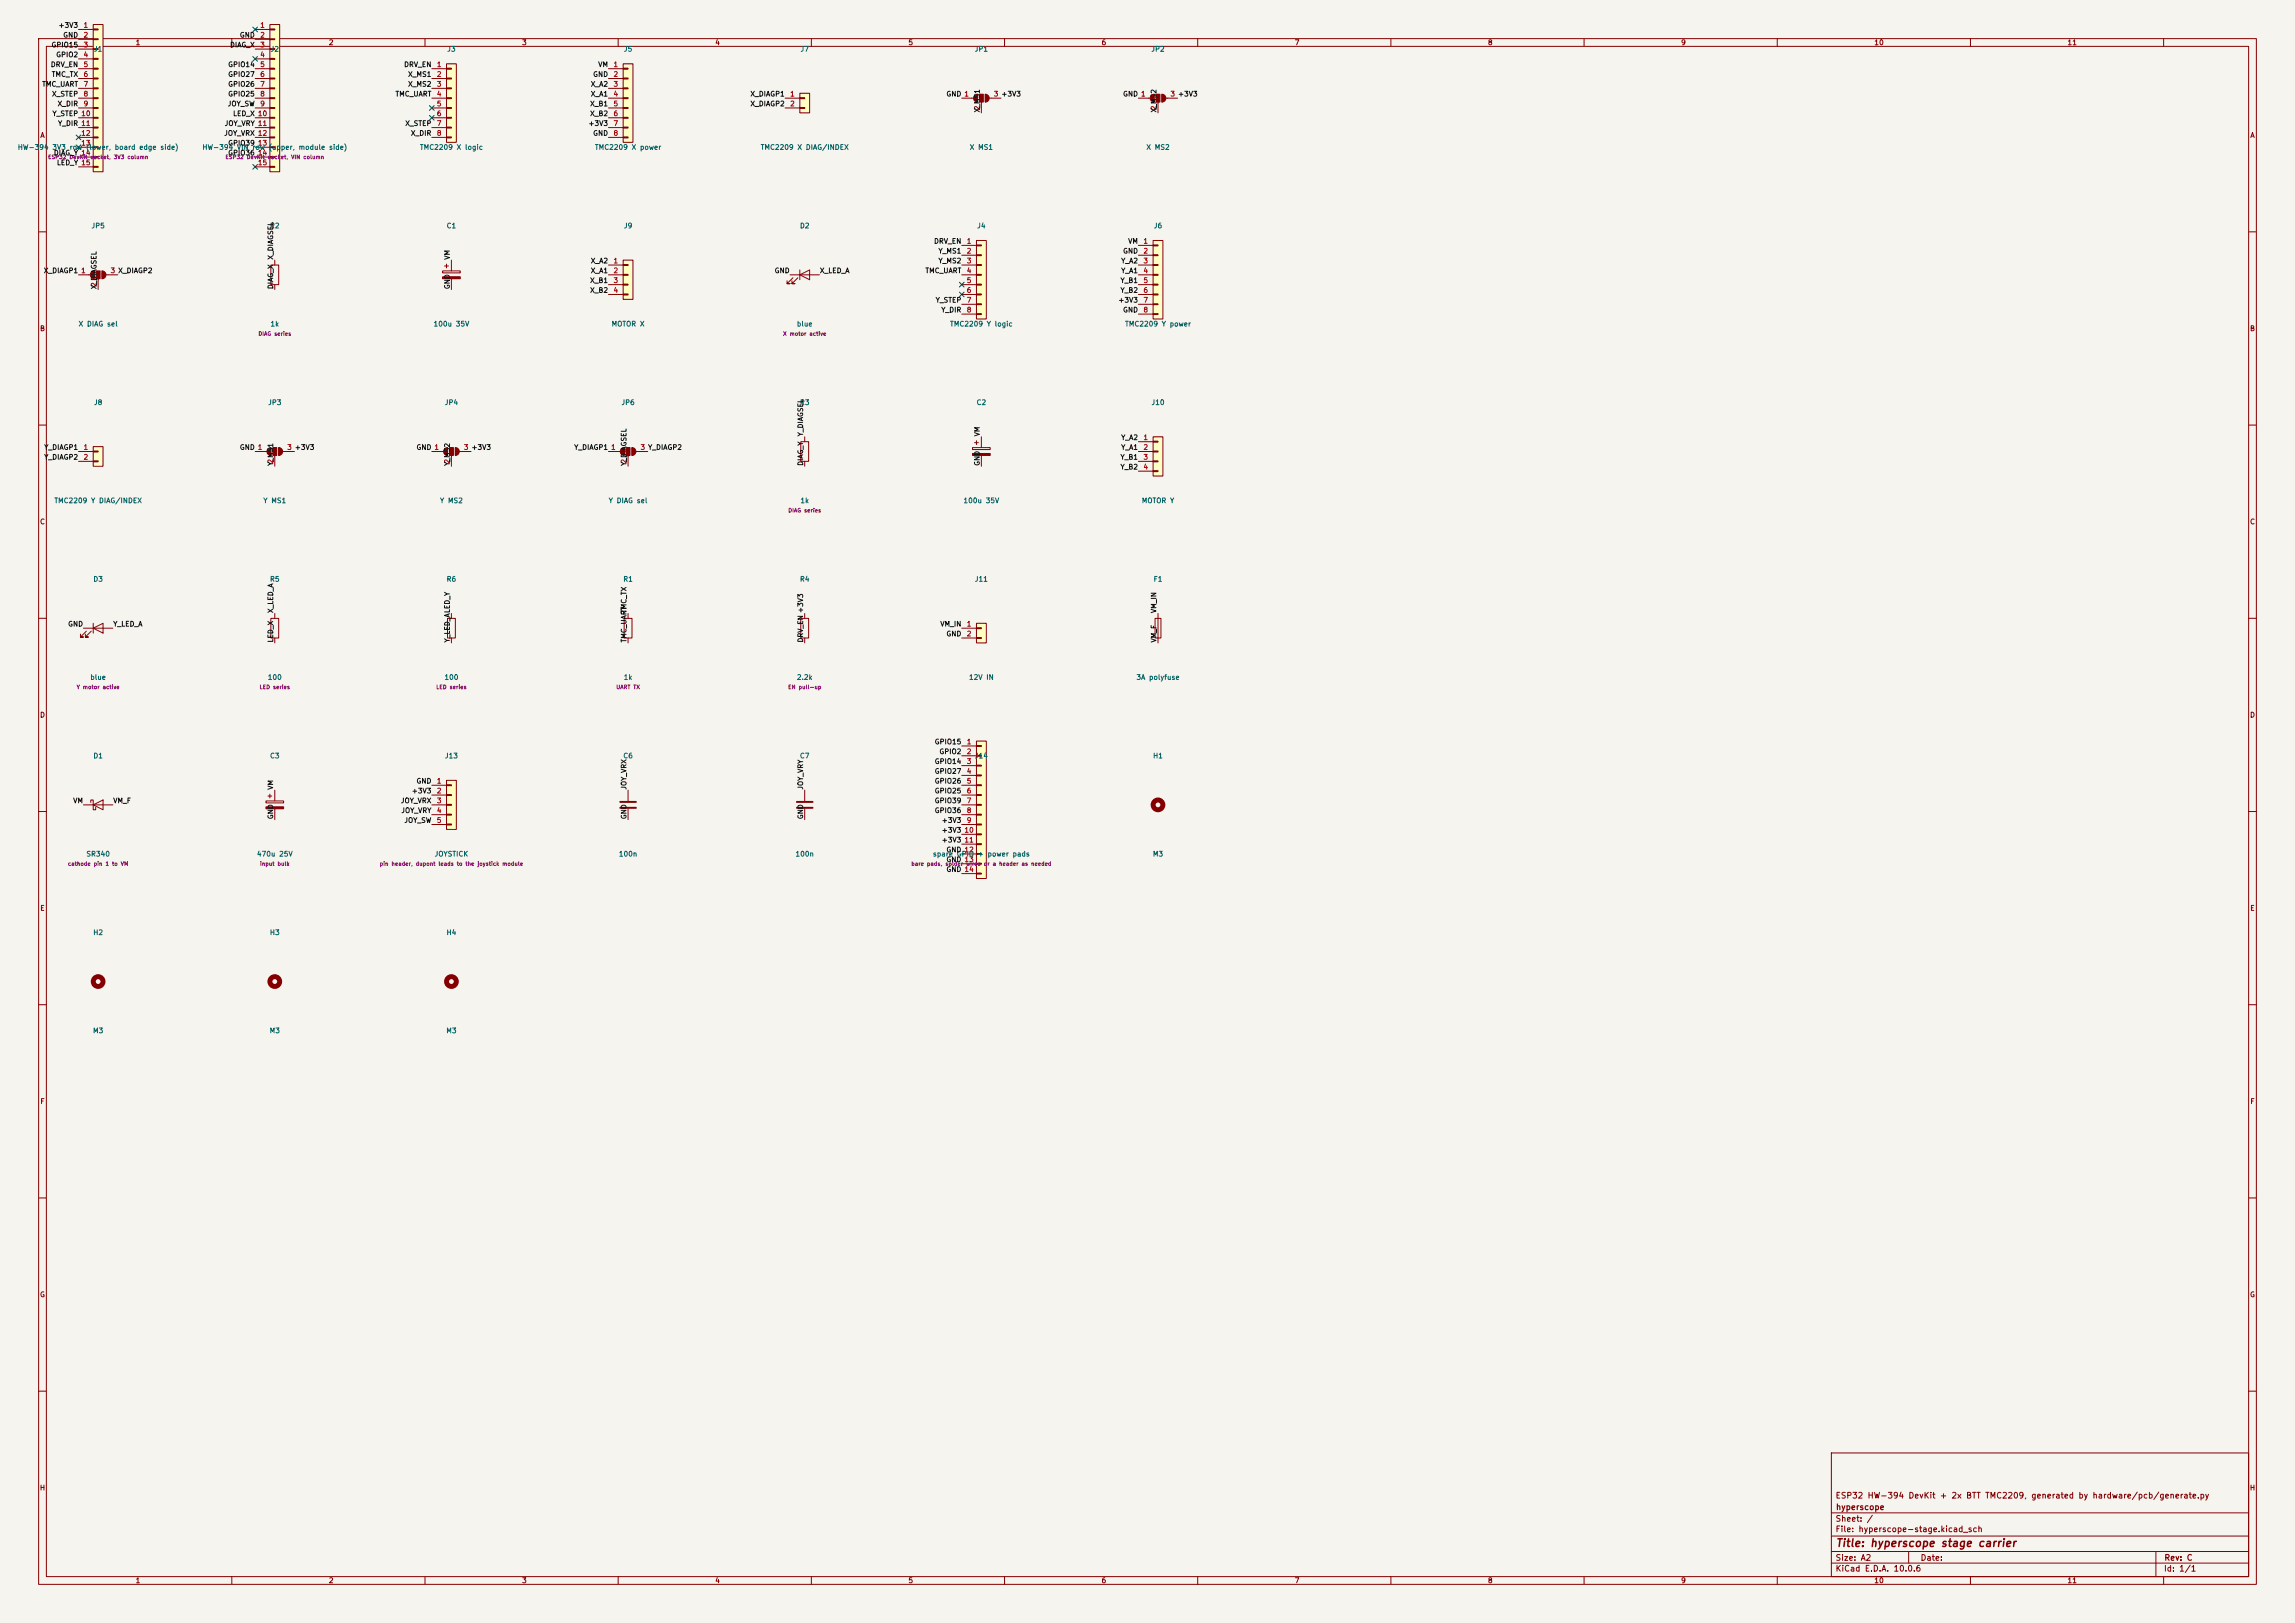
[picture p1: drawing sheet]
<svg xmlns="http://www.w3.org/2000/svg" width="594mm" height="420mm" viewBox="0 0 594 420" stroke-linecap="round" stroke-linejoin="round" font-family="sans-serif">
<defs><g id="words">
<text font-size="2" fill="#840000" x="475" y="400.8">Title: hyperscope stage carrier</text>
<g font-size="1.5" fill="#840000">
<text x="475" y="388.1">ESP32 HW-394 DevKit + 2x BTT TMC2209, generated by hardware/pcb/generate.py</text>
<text x="475" y="394.1">Sheet: /</text>
<text x="475.1" y="391.1">hyperscope</text>
<text x="475" y="396.8">File: hyperscope-stage.kicad_sch</text>
<text x="475" y="407">KiCad E.D.A. 10.0.6</text>
<text x="475" y="404.2">Size: A2</text>
<text x="497" y="404.2">Date:</text>
<text x="560" y="407">Id: 1/1</text>
<text x="560.1" y="404.2">Rev: C</text>
</g>
<g font-size="1.3" fill="#0f0f0f">
<text x="15" y="7.5">+3V3</text>
<text x="16.2" y="10">GND</text>
<text x="61.9" y="10">GND</text>
<text x="13" y="17.7">DRV_EN</text>
<text x="13.2" y="12.6">GPIO15</text>
<text x="14.4" y="15.1">GPIO2</text>
<text x="58.9" y="17.7">GPIO14</text>
<text x="59.4" y="12.6">DIAG_X</text>
<text x="104.5" y="17.7">DRV_EN</text>
<text x="154.7" y="17.7">VM</text>
<text x="10.8" y="22.7">TMC_UART</text>
<text x="13.3" y="20.2">TMC_TX</text>
<text x="58.9" y="22.7">GPIO26</text>
<text x="58.9" y="20.2">GPIO27</text>
<text x="105.5" y="22.7">X_MS2</text>
<text x="105.5" y="20.2">X_MS1</text>
<text x="152.8" y="22.7">X_A2</text>
<text x="153.4" y="20.2">GND</text>
<text x="13.3" y="25.3">X_STEP</text>
<text x="14.8" y="27.8">X_DIR</text>
<text x="58.8" y="27.8">JOY_SW</text>
<text x="58.9" y="25.3">GPIO25</text>
<text x="102.2" y="25.3">TMC_UART</text>
<text x="152.6" y="27.8">X_B1</text>
<text x="152.8" y="25.3">X_A1</text>
<text x="194.1" y="27.8">X_DIAGP2</text>
<text x="194.1" y="25.3">X_DIAGP1</text>
<text x="244.8" y="25.3">GND 1</text>
<text x="253.9" y="29.2" transform="rotate(-90 253.9 29.2)">X_MS1</text>
<text x="290.5" y="25.3">GND 1</text>
<text x="299.6" y="29.2" transform="rotate(-90 299.6 29.2)">X_MS2</text>
<text x="13.4" y="30.4">Y_STEP 10</text>
<text x="14.9" y="32.9">Y_DIR 11</text>
<text x="57.9" y="35.4">JOY_VRX 12</text>
<text x="58" y="32.9">JOY_VRY 11</text>
<text x="60.2" y="30.4">LED_X 10</text>
<text x="104.8" y="32.9">X_STEP</text>
<text x="106.2" y="35.4">X_DIR</text>
<text x="152.2" y="32.9">+3V3</text>
<text x="152.6" y="30.4">X_B2</text>
<text x="153.4" y="35.4">GND</text>
<text x="13.8" y="40.5">DIAG_Y 14</text>
<text x="58.9" y="38">GPIO39</text>
<text x="58.9" y="40.5">GPIO36</text>
<text x="14.6" y="43.1">LED_Y 15</text>
<text x="241.6" y="63.4">DRV_EN</text>
<text x="242.8" y="65.9">Y_MS1</text>
<text x="290.5" y="65.9">GND</text>
<text x="291.9" y="63.4">VM</text>
<text x="11.2" y="71">X_DIAGP1</text>
<text x="71" y="67.3" transform="rotate(-90 71 67.3)">X_DIAGSEL</text>
<text x="116.7" y="67.3" transform="rotate(-90 116.7 67.3)">VM</text>
<text x="152.8" y="68.5">X_A2</text>
<text x="152.8" y="71">X_A1</text>
<text x="200.4" y="71">GND</text>
<text x="212.1" y="71">X_LED_A</text>
<text x="239.4" y="71">TMC_UART</text>
<text x="242.8" y="68.5">Y_MS2</text>
<text x="290.1" y="71">Y_A1</text>
<text x="290.1" y="68.5">Y_A2</text>
<text x="25.3" y="75" transform="rotate(-90 25.3 75)">X_DIAGSEL</text>
<text x="71" y="75" transform="rotate(-90 71 75)">DIAG_X</text>
<text x="116.7" y="75" transform="rotate(-90 116.7 75)">GND</text>
<text x="152.6" y="73.5">X_B1</text>
<text x="152.6" y="76.1">X_B2</text>
<text x="289.9" y="73.5">Y_B1</text>
<text x="289.9" y="76.1">Y_B2</text>
<text x="242" y="78.6">Y_STEP</text>
<text x="243.5" y="81.2">Y_DIR</text>
<text x="289.3" y="78.6">+3V3</text>
<text x="290.5" y="81.2">GND</text>
<text x="208.2" y="113.1" transform="rotate(-90 208.2 113.1)">Y_DIAGSEL</text>
<text x="253.9" y="113.1" transform="rotate(-90 253.9 113.1)">VM</text>
<text x="11.3" y="116.7">Y_DIAGP1</text>
<text x="11.3" y="119.3">Y_DIAGP2</text>
<text x="61.9" y="116.7">GND 1</text>
<text x="107.7" y="116.7">GND 1</text>
<text x="148.5" y="116.7">Y_DIAGP1</text>
<text x="289.9" y="119.3">Y_B1</text>
<text x="290.1" y="114.2">Y_A2</text>
<text x="290.1" y="116.7">Y_A1</text>
<text x="71" y="120.7" transform="rotate(-90 71 120.7)">Y_MS1</text>
<text x="116.7" y="120.7" transform="rotate(-90 116.7 120.7)">Y_MS2</text>
<text x="162.4" y="120.7" transform="rotate(-90 162.4 120.7)">Y_DIAGSEL</text>
<text x="208.2" y="120.7" transform="rotate(-90 208.2 120.7)">DIAG_Y</text>
<text x="253.9" y="120.7" transform="rotate(-90 253.9 120.7)">GND</text>
<text x="289.9" y="121.8">Y_B2</text>
<text x="71" y="158.8" transform="rotate(-90 71 158.8)">X_LED_A</text>
<text x="162.4" y="158.8" transform="rotate(-90 162.4 158.8)">TMC_TX</text>
<text x="299.6" y="158.8" transform="rotate(-90 299.6 158.8)">VM_IN</text>
<text x="17.5" y="162.4">GND</text>
<text x="29.2" y="162.4">Y_LED_A</text>
<text x="71" y="166.4" transform="rotate(-90 71 166.4)">LED_X</text>
<text x="116.7" y="166.4" transform="rotate(-90 116.7 166.4)">Y_LED_ALED_Y</text>
<text x="162.4" y="166.4" transform="rotate(-90 162.4 166.4)">TMC_UART</text>
<text x="208.2" y="166.4" transform="rotate(-90 208.2 166.4)">DRV_EN +3V3</text>
<text x="243.2" y="162.4">VM_IN</text>
<text x="244.8" y="165">GND</text>
<text x="299.6" y="166.4" transform="rotate(-90 299.6 166.4)">VM_F</text>
<text x="241.8" y="192.9">GPIO15</text>
<text x="241.8" y="198">GPIO14</text>
<text x="243" y="195.5">GPIO2</text>
<text x="107.7" y="203.1">GND</text>
<text x="241.8" y="203.1">GPIO26</text>
<text x="241.8" y="200.5">GPIO27</text>
<text x="18.8" y="208.2">VM</text>
<text x="29.2" y="208.2">VM_F</text>
<text x="71" y="204.5" transform="rotate(-90 71 204.5)">VM</text>
<text x="103.6" y="208.2">JOY_VRX</text>
<text x="106.5" y="205.6">+3V3</text>
<text x="162.4" y="204.5" transform="rotate(-90 162.4 204.5)">JOY_VRX</text>
<text x="208.2" y="204.5" transform="rotate(-90 208.2 204.5)">JOY_VRY</text>
<text x="241.8" y="205.6">GPIO25</text>
<text x="241.8" y="208.2">GPIO39</text>
<text x="71" y="212.1" transform="rotate(-90 71 212.1)">GND</text>
<text x="103.7" y="210.7">JOY_VRY</text>
<text x="104.5" y="213.2">JOY_SW</text>
<text x="162.4" y="212.1" transform="rotate(-90 162.4 212.1)">GND</text>
<text x="208.2" y="212.1" transform="rotate(-90 208.2 212.1)">GND</text>
<text x="241.8" y="210.7">GPIO36</text>
<text x="243.6" y="213.2">+3V3</text>
<text x="243.6" y="215.8">+3V3</text>
<text x="243.6" y="218.3">+3V3</text>
<text x="244.8" y="220.9">GND 12</text>
<text x="244.8" y="223.4">GND 13</text>
<text x="244.8" y="225.9">GND 14</text>
</g>
<g font-size="1.3" fill="#a90000">
<text x="21.5" y="7.5">1</text>
<text x="21.5" y="10">2</text>
<text x="67.2" y="7.5">1</text>
<text x="67.2" y="10">2</text>
<text x="21.5" y="12.6">3</text>
<text x="21.5" y="15.1">4</text>
<text x="21.5" y="17.6">5</text>
<text x="67.2" y="12.6">3</text>
<text x="67.2" y="15.1">4</text>
<text x="67.2" y="17.6">5</text>
<text x="112.9" y="17.6">1</text>
<text x="158.7" y="17.6">1</text>
<text x="21.5" y="20.2">6</text>
<text x="21.5" y="22.7">7</text>
<text x="67.2" y="20.2">6</text>
<text x="67.2" y="22.7">7</text>
<text x="112.9" y="20.2">2</text>
<text x="112.9" y="22.7">3</text>
<text x="158.7" y="20.2">2</text>
<text x="158.7" y="22.7">3</text>
<text x="21.5" y="25.3">8</text>
<text x="21.5" y="27.8">9</text>
<text x="67.2" y="25.3">8</text>
<text x="67.2" y="27.8">9</text>
<text x="112.9" y="25.3">4</text>
<text x="112.9" y="27.8">5</text>
<text x="158.7" y="25.3">4</text>
<text x="158.7" y="27.8">5</text>
<text x="204.4" y="25.3">1</text>
<text x="204.4" y="27.8">2</text>
<text x="253.9" y="28.7" transform="rotate(-90 253.9 28.7)">2</text>
<text x="257.1" y="25.3">3 +3V3</text>
<text x="299.6" y="28.7" transform="rotate(-90 299.6 28.7)">2</text>
<text x="302.8" y="25.3">3 +3V3</text>
<text x="20.9" y="35.4">12</text>
<text x="112.9" y="30.3">6</text>
<text x="112.9" y="32.9">7</text>
<text x="112.9" y="35.4">8</text>
<text x="158.7" y="30.3">6</text>
<text x="158.7" y="32.9">7</text>
<text x="158.7" y="35.4">8</text>
<text x="20.9" y="38">13</text>
<text x="66.6" y="38">13</text>
<text x="66.6" y="40.5">14</text>
<text x="66.6" y="43">15</text>
<text x="250.1" y="63.4">1</text>
<text x="250.1" y="65.9">2</text>
<text x="295.8" y="63.4">1</text>
<text x="295.8" y="65.9">2</text>
<text x="20.9" y="71">1</text>
<text x="28.5" y="71">3 X_DIAGP2</text>
<text x="158.7" y="68.4">1</text>
<text x="158.7" y="71">2</text>
<text x="250.1" y="68.4">3</text>
<text x="250.1" y="71">4</text>
<text x="295.8" y="68.4">3</text>
<text x="295.8" y="71">4</text>
<text x="25.3" y="74.4" transform="rotate(-90 25.3 74.4)">2</text>
<text x="158.7" y="73.5">3</text>
<text x="158.7" y="76.1">4</text>
<text x="250.1" y="73.5">5</text>
<text x="250.1" y="76.1">6</text>
<text x="295.8" y="73.5">5</text>
<text x="295.8" y="76.1">6</text>
<text x="250.1" y="78.6">7</text>
<text x="250.1" y="81.1">8</text>
<text x="295.8" y="78.6">7</text>
<text x="295.8" y="81.1">8</text>
<text x="21.5" y="116.7">1</text>
<text x="21.5" y="119.2">2</text>
<text x="74.2" y="116.7">3 +3V3</text>
<text x="119.9" y="116.7">3 +3V3</text>
<text x="158" y="116.7">1</text>
<text x="165.6" y="116.7">3 Y_DIAGP2</text>
<text x="295.8" y="114.2">1</text>
<text x="295.8" y="116.7">2</text>
<text x="295.8" y="119.2">3</text>
<text x="71" y="120.1" transform="rotate(-90 71 120.1)">2</text>
<text x="116.7" y="120.1" transform="rotate(-90 116.7 120.1)">2</text>
<text x="162.4" y="120.1" transform="rotate(-90 162.4 120.1)">2</text>
<text x="295.8" y="121.8">4</text>
<text x="250.1" y="162.4">1</text>
<text x="250.1" y="165">2</text>
<text x="250.1" y="192.9">1</text>
<text x="250.1" y="195.4">2</text>
<text x="250.1" y="198">3</text>
<text x="112.9" y="203.1">1</text>
<text x="250.1" y="200.5">4</text>
<text x="250.1" y="203.1">5</text>
<text x="112.9" y="205.6">2</text>
<text x="112.9" y="208.1">3</text>
<text x="250.1" y="205.6">6</text>
<text x="250.1" y="208.1">7</text>
<text x="112.9" y="210.7">4</text>
<text x="112.9" y="213.2">5</text>
<text x="249.5" y="215.8">10</text>
<text x="250.1" y="210.7">8</text>
<text x="250.1" y="213.2">9</text>
<text x="249.5" y="218.3">11</text>
</g>
<g font-size="1.3" fill="#840000">
<text x="35" y="12">1</text>
<text x="85" y="12">2</text>
<text x="135" y="12">3</text>
<text x="185" y="12">4</text>
<text x="235" y="12">5</text>
<text x="285" y="12">6</text>
<text x="335" y="12">7</text>
<text x="385" y="12">8</text>
<text x="435" y="12">9</text>
<text x="485" y="12">10</text>
<text x="535" y="12">11</text>
<text x="10.3" y="36">A</text>
<text x="582.3" y="36">A</text>
<text x="10.2" y="86">B</text>
<text x="582.2" y="86">B</text>
<text x="10.2" y="136">C</text>
<text x="582.2" y="136">C</text>
<text x="10.2" y="186">D</text>
<text x="582.2" y="186">D</text>
<text x="10.3" y="236">E</text>
<text x="582.3" y="236">E</text>
<text x="10.3" y="286">F</text>
<text x="582.3" y="286">F</text>
<text x="10.2" y="336">G</text>
<text x="582.2" y="336">G</text>
<text x="10.2" y="386">H</text>
<text x="582.2" y="386">H</text>
<text x="35" y="410">1</text>
<text x="85" y="410">2</text>
<text x="135" y="410">3</text>
<text x="185" y="410">4</text>
<text x="235" y="410">5</text>
<text x="285" y="410">6</text>
<text x="335" y="410">7</text>
<text x="385" y="410">8</text>
<text x="435" y="410">9</text>
<text x="485" y="410">10</text>
<text x="535" y="410">11</text>
</g>
<g font-size="1.3" fill="#006464">
<text x="24.2" y="13.7">J1</text>
<text x="69.9" y="13.7">J2</text>
<text x="115.6" y="13.7">J3</text>
<text x="161.3" y="13.7">J5</text>
<text x="207.1" y="13.7">J7</text>
<text x="252.1" y="13.7">JP1</text>
<text x="297.9" y="13.7">JP2</text>
<text x="4.5" y="39.1">HW-394 3V3 row (lower, board edge side)</text>
<text x="52.2" y="39.1">HW-394 VIN row (upper, module side)</text>
<text x="108.5" y="39.1">TMC2209 X logic</text>
<text x="153.8" y="39.1">TMC2209 X power</text>
<text x="196.8" y="39.1">TMC2209 X DIAG/INDEX</text>
<text x="250.8" y="39.1">X MS1</text>
<text x="296.6" y="39.1">X MS2</text>
<text x="23.5" y="59.4">JP5</text>
<text x="69.8" y="59.4">R2</text>
<text x="115.5" y="59.4">C1</text>
<text x="161.3" y="59.4">J9</text>
<text x="206.9" y="59.4">D2</text>
<text x="252.8" y="59.4">J4</text>
<text x="298.5" y="59.4">J6</text>
<text x="20.2" y="84.8">X DIAG sel</text>
<text x="69.9" y="84.8">1k</text>
<text x="112.1" y="84.8">100u 35V</text>
<text x="158.2" y="84.8">MOTOR X</text>
<text x="206.1" y="84.8">blue</text>
<text x="245.8" y="84.8">TMC2209 Y logic</text>
<text x="291.1" y="84.8">TMC2209 Y power</text>
<text x="24.2" y="105.1">J8</text>
<text x="69.3" y="105.1">JP3</text>
<text x="115" y="105.1">JP4</text>
<text x="160.7" y="105.1">JP6</text>
<text x="206.9" y="105.1">R3</text>
<text x="252.6" y="105.1">C2</text>
<text x="297.9" y="105.1">J10</text>
<text x="13.9" y="130.5">TMC2209 Y DIAG/INDEX</text>
<text x="68" y="130.5">Y MS1</text>
<text x="113.7" y="130.5">Y MS2</text>
<text x="157.4" y="130.5">Y DIAG sel</text>
<text x="207" y="130.5">1k</text>
<text x="249.2" y="130.5">100u 35V</text>
<text x="295.4" y="130.5">MOTOR Y</text>
<text x="24" y="150.8">D3</text>
<text x="69.8" y="150.8">R5</text>
<text x="115.5" y="150.8">R6</text>
<text x="161.2" y="150.8">R1</text>
<text x="206.9" y="150.8">R4</text>
<text x="252.2" y="150.8">J11</text>
<text x="298.4" y="150.8">F1</text>
<text x="23.2" y="176.2">blue</text>
<text x="69.2" y="176.2">100</text>
<text x="114.9" y="176.2">100</text>
<text x="161.3" y="176.2">1k</text>
<text x="206.1" y="176.2">2.2k</text>
<text x="250.7" y="176.2">12V IN</text>
<text x="294" y="176.2">3A polyfuse</text>
<text x="24" y="196.5">D1</text>
<text x="69.8" y="196.5">C3</text>
<text x="115" y="196.5">J13</text>
<text x="161.2" y="196.5">C6</text>
<text x="206.9" y="196.5">C7</text>
<text x="252.2" y="196.5">J14</text>
<text x="298.3" y="196.5">H1</text>
<text x="22.2" y="221.9">SR340</text>
<text x="66.4" y="221.9">470u 25V</text>
<text x="112.4" y="221.9">JOYSTICK</text>
<text x="160" y="221.9">100n</text>
<text x="205.8" y="221.9">100n</text>
<text x="241.3" y="221.9">spare GPIO</text>
<text x="252.9" y="221.9">+</text>
<text x="255.5" y="221.9">power pads</text>
<text x="298.3" y="221.9">M3</text>
<text x="24" y="242.3">H2</text>
<text x="69.7" y="242.3">H3</text>
<text x="115.4" y="242.3">H4</text>
<text x="23.9" y="267.7">M3</text>
<text x="69.7" y="267.7">M3</text>
<text x="115.4" y="267.7">M3</text>
</g>
<g font-size="1" fill="#840084">
<text x="12.3" y="41.4">ESP32 DevKit socket, 3V3 column</text>
<text x="58.2" y="41.4">ESP32 DevKit socket, VIN column</text>
<text x="66.8" y="87.1">DIAG series</text>
<text x="202.6" y="87.1">X motor active</text>
<text x="203.9" y="132.8">DIAG series</text>
<text x="19.7" y="178.6">Y motor active</text>
<text x="67.1" y="178.6">LED series</text>
<text x="112.8" y="178.6">LED series</text>
<text x="159.4" y="178.6">UART TX</text>
<text x="203.9" y="178.6">EN pull-up</text>
<text x="17.5" y="224.3">cathode pin 1 to VM</text>
<text x="67.2" y="224.3">input bulk</text>
<text x="98.2" y="224.3">pin header, dupont leads to the joystick module</text>
<text x="235.8" y="224.3">bare pads, solder wires or a header as needed</text>
</g>
</g></defs>
<path d="M0 0h594v420h-594z" fill="#f5f4ef" stroke="#f5f4ef" stroke-width=".26"/>
<g fill="none" stroke="#840000" stroke-width=".26">
<path d="M10 10h574v400h-574zM12 12h570v396h-570zM60 10v2M110 10v2M160 10v2M210 10v2M260 10v2M310 10v2M360 10v2M410 10v2M460 10v2M510 10v2"/>
<path d="M560 10v2M10 60h2M582 60h2M10 110h2M582 110h2M10 160h2M582 160h2M10 210h2M582 210h2M10 260h2M582 260h2M10 310h2"/>
<path d="M582 310h2M10 360h2M474 376h108v32h-108zM582 360h2M474 397.5h108M474 391.5h108M60 408v2M110 408v2M160 408v2M210 408v2M260 408v2M310 408v2"/>
<path d="M360 408v2M410 408v2M460 408v2M474 404.5h108M474 401.5h108M494 401.5v3M510 408v2M558 401.5v6.5M560 408v2"/>
</g>
<path d="M115.6 16.5h2.5v20.3h-2.5z" fill="#ffffc2"/>
<g fill="none" stroke="#840000" stroke-width=".26">
<path d="M111.8 17.8h3.8M115.6 16.5h2.5v20.3h-2.5zM115.6 17.7h1.2v.2h-1.2zM111.8 20.3h3.8M111.8 22.9h3.8M111.8 25.4h3.8M111.8 27.9h3.8M111.8 30.5h3.8M111.8 33h3.8M111.8 35.6h3.8M115.6 20.2h1.2v.2h-1.2zM115.6 22.7h1.2v.3h-1.2z"/>
<path d="M115.6 25.3h1.2v.2h-1.2zM115.6 27.8h1.2v.3h-1.2zM115.6 30.4h1.2v.2h-1.2zM115.6 32.9h1.2v.2h-1.2zM115.6 35.4h1.2v.3h-1.2z"/>
</g>
<path d="M298.4 113h2.6v10.2h-2.6z" fill="#ffffc2"/>
<g fill="none" stroke="#840000" stroke-width=".26">
<path d="M251.7 115.8h4.6v.5h-4.6zM252.2 114.6h1M252.7 114v1.1M254 113v2.8M254 117.9v2.8M294.6 114.3h3.8M294.6 116.8h3.8M294.6 119.4h3.8M298.4 113h2.6v10.2h-2.6zM298.4 114.2h1.3v.2h-1.3zM298.4 116.7h1.3v.3h-1.3zM298.4 119.3h1.3v.2h-1.3z"/>
<path d="M294.6 121.9h3.8M298.4 121.8h1.3v.2h-1.3z"/>
</g>
<path d="M251.7 117.3h4.6v.6h-4.6z" fill="#840000" stroke="#840000" stroke-width=".26"/>
<path d="M115.6 201.9h2.5v12.7h-2.5z" fill="#ffffc2"/>
<g fill="none" stroke="#840000" stroke-width=".26">
<path d="M116.8 158.8v1.2M162.6 158.8v1.2M115.8 160h2.1v5.1h-2.1zM116.8 165.1v1.3M161.5 160h2.1v5.1h-2.1zM162.6 165.1v1.3M111.8 203.2h3.8M111.8 205.7h3.8M111.8 208.3h3.8M111.8 210.8h3.8M111.8 213.4h3.8M115.6 201.9h2.5v12.7h-2.5z"/>
<path d="M115.6 203.1h1.2v.2h-1.2zM115.6 205.6h1.2v.3h-1.2zM115.6 208.2h1.2v.2h-1.2zM115.6 210.7h1.2v.2h-1.2zM115.6 213.2h1.2v.3h-1.2z"/>
</g>
<path d="M24.1 6.4h2.6v38.1h-2.6z" fill="#ffffc2"/>
<g fill="none" stroke="#840000" stroke-width=".26">
<path d="M20.3 7.6h3.8M20.3 10.2h3.8M20.3 12.7h3.8M20.3 15.2h3.8M20.3 17.8h3.8M24.1 6.4h2.6v38.1h-2.6zM24.1 7.5h1.3v.2h-1.3zM24.1 10h1.3v.3h-1.3zM24.1 12.6h1.3v.2h-1.3zM24.1 15.1h1.3v.3h-1.3zM24.1 17.7h1.3v.2h-1.3zM20.3 20.3h3.8"/>
<path d="M20.3 22.9h3.8M20.3 25.4h3.8M20.3 27.9h3.8M20.3 30.5h3.8M20.3 33h3.8M20.3 35.6h3.8M20.3 38.1h3.8M24.1 20.2h1.3v.2h-1.3zM24.1 22.7h1.3v.3h-1.3zM24.1 25.3h1.3v.2h-1.3zM24.1 27.8h1.3v.3h-1.3zM24.1 30.4h1.3v.2h-1.3z"/>
<path d="M24.1 32.9h1.3v.2h-1.3zM24.1 35.4h1.3v.3h-1.3zM24.1 38h1.3v.2h-1.3zM20.3 40.6h3.8M20.3 43.2h3.8M24.1 40.5h1.3v.3h-1.3zM24.1 43.1h1.3v.2h-1.3zM71.1 158.8v1.2M21.6 162.6h7.6M22.4 163.3l-1.6 1.5h.8h-.8v-.7M23.6 163.3l-1.5 1.5h.8h-.8v-.7M24.1 162.6l2.6-1.3v2.5z"/>
<path d="M24.1 161.3v2.5M70.1 160h2v5.1h-2zM71.1 165.1v1.3M21.6 208.3h7.6M23.5 207.6v-.6h.6v2.6h.7v-.7M24.1 208.3l2.6-1.3v2.6zM68.8 207.3h4.6v.5h-4.6zM69.3 206h1.1M69.8 205.5v1M71.1 204.5v2.8M71.1 209.3v2.8M162.6 204.5v2.8"/>
<path d="M162.6 209.3v2.8"/>
</g>
<path d="M160.5 207.5h4.1M160.5 209h4.1" fill="none" stroke="#840000" stroke-width=".51"/>
<g fill="none" stroke="#840000" stroke-width="1.3">
<circle cx="25.4" cy="254" r="1.27"/>
<circle cx="71.1" cy="254" r="1.27"/>
</g>
<path d="M68.8 208.8h4.6v.5h-4.6z" fill="#840000" stroke="#840000" stroke-width=".26"/>
<path d="M161.3 67.3h2.5v10.2h-2.5z" fill="#ffffc2"/>
<g fill="none" stroke="#840000" stroke-width=".26">
<path d="M20.3 71.1h3.1M24.4 70.1v2M25.4 72.1v2.8M26.4 70.1v2M27.4 71.1h3.1M70.1 68.6h2v5.1h-2zM71.1 67.3v1.3M71.1 73.7v1.2M114.6 70.1h4.5v.5h-4.5zM115.1 68.8h1M115.6 68.3v1M116.8 67.3v2.8"/>
<path d="M116.8 72.1v2.8M157.5 68.6h3.8M157.5 71.1h3.8M157.5 73.7h3.8M157.5 76.2h3.8M161.3 67.3h2.5v10.2h-2.5zM161.3 68.5h1.3v.2h-1.3zM161.3 71h1.3v.2h-1.3zM161.3 73.5h1.3v.3h-1.3zM161.3 76.1h1.3v.2h-1.3zM66 116.8h3.1M70.1 115.8v2.1"/>
<path d="M71.1 117.9v2.8M72.1 115.8v2.1M73.2 116.8h3M111.8 116.8h3M115.8 115.8v2.1M116.8 117.9v2.8M117.9 115.8v2.1M118.9 116.8h3M157.5 116.8h3M161.5 115.8v2.1M162.6 117.9v2.8M163.6 115.8v2.1"/>
<path d="M164.6 116.8h3"/>
</g>
<g fill="#840000" stroke="#840000" stroke-width=".26">
<path d="M114.6 71.6h4.5v.5h-4.5z"/>
<path d="M115.1 116.1l.7-.3v2.1a1.02 1.02 0 0 1-.9-.7 1.02 1.02 0 0 1 .2-1.1z"/>
<path d="M116.3 115.8h1v2.1h-1z"/>
<path d="M117.9 115.8a1.02 1.02 0 0 1 1 1 1.02 1.02 0 0 1-1 1.1z"/>
<path d="M69.4 116.1l.7-.3v2.1a1.02 1.02 0 0 1-.9-.7 1.02 1.02 0 0 1 .2-1.1z"/>
<path d="M70.6 115.8h1v2.1h-1z"/>
<path d="M72.1 115.8a1.02 1.02 0 0 1 1 1 1.02 1.02 0 0 1-1 1.1z"/>
<path d="M160.8 116.1l.7-.3v2.1a1.02 1.02 0 0 1-.9-.7 1.02 1.02 0 0 1 .2-1.1z"/>
<path d="M162.1 115.8h1v2.1h-1z"/>
<path d="M163.6 115.8a1.02 1.02 0 0 1 1 1 1.02 1.02 0 0 1-1 1.1z"/>
<path d="M23.7 70.4l.7-.3v2a1.02 1.02 0 0 1-.9-.6 1.02 1.02 0 0 1 .2-1.1z"/>
<path d="M24.9 70.1h1v2h-1z"/>
<path d="M26.4 70.1a1.02 1.02 0 0 1 1 1 1.02 1.02 0 0 1-1 1z"/>
</g>
<path d="M24.1 115.6h2.6v5.1h-2.6z" fill="#ffffc2"/>
<path d="M20.3 116.8h3.8M20.3 119.4h3.8M24.1 115.6h2.6v5.1h-2.6zM24.1 116.7h1.3v.3h-1.3zM24.1 119.3h1.3v.2h-1.3zM299.7 158.8v7.6M299 160h1.5v5.1h-1.5zM208.3 204.5v2.8M208.3 209.3v2.8" fill="none" stroke="#840000" stroke-width=".26"/>
<path d="M206.2 207.5h4.1M206.2 209h4.1" fill="none" stroke="#840000" stroke-width=".51"/>
<path d="M252.7 161.3h2.6v5.1h-2.6z" fill="#ffffc2"/>
<path d="M248.9 162.6h3.8M248.9 165.1h3.8M252.7 161.3h2.6v5.1h-2.6zM252.7 162.4h1.3v.3h-1.3zM252.7 165h1.3v.2h-1.3z" fill="none" stroke="#840000" stroke-width=".26"/>
<circle cx="299.7" cy="208.3" r="1.27" fill="none" stroke="#840000" stroke-width="1.3"/>
<path d="M252.7 191.8h2.6v35.5h-2.6z" fill="#ffffc2"/>
<g fill="none" stroke="#840000" stroke-width=".26">
<path d="M207.3 114.3h2v5.1h-2zM208.3 113v1.3M208.3 119.4v1.3M208.3 158.8v1.2M207.3 160h2v5.1h-2zM208.3 165.1v1.3M248.9 193h3.8M248.9 195.6h3.8M248.9 198.1h3.8M252.7 191.8h2.6v35.5h-2.6zM252.7 192.9h1.3v.3h-1.3zM252.7 195.5h1.3v.2h-1.3z"/>
<path d="M252.7 198h1.3v.2h-1.3zM248.9 200.7h3.8M248.9 203.2h3.8M248.9 205.7h3.8M248.9 208.3h3.8M248.9 210.8h3.8M248.9 213.4h3.8M248.9 215.9h3.8M248.9 218.4h3.8M252.7 200.5h1.3v.3h-1.3zM252.7 203.1h1.3v.2h-1.3zM252.7 205.6h1.3v.3h-1.3z"/>
<path d="M252.7 208.2h1.3v.2h-1.3zM252.7 210.7h1.3v.2h-1.3zM252.7 213.2h1.3v.3h-1.3zM252.7 215.8h1.3v.2h-1.3zM252.7 218.3h1.3v.3h-1.3zM248.9 221h3.8M248.9 223.5h3.8M248.9 226.1h3.8M252.7 220.9h1.3v.2h-1.3zM252.7 223.4h1.3v.2h-1.3zM252.7 225.9h1.3v.3h-1.3z"/>
</g>
<path d="M69.8 6.4h2.6v38.1h-2.6z" fill="#ffffc2"/>
<g fill="none" stroke="#840000" stroke-width=".26">
<path d="M66 7.6h3.8M66 10.2h3.8M66 12.7h3.8M66 15.2h3.8M66 17.8h3.8M69.8 6.4h2.6v38.1h-2.6zM69.8 7.5h1.3v.2h-1.3zM69.8 10h1.3v.3h-1.3zM69.8 12.6h1.3v.2h-1.3zM69.8 15.1h1.3v.3h-1.3zM69.8 17.7h1.3v.2h-1.3zM66 20.3h3.8"/>
<path d="M66 22.9h3.8M66 25.4h3.8M66 27.9h3.8M66 30.5h3.8M66 33h3.8M66 35.6h3.8M66 38.1h3.8M69.8 20.2h1.3v.2h-1.3zM69.8 22.7h1.3v.3h-1.3zM69.8 25.3h1.3v.2h-1.3zM69.8 27.8h1.3v.3h-1.3zM69.8 30.4h1.3v.2h-1.3z"/>
<path d="M69.8 32.9h1.3v.2h-1.3zM69.8 35.4h1.3v.3h-1.3zM69.8 38h1.3v.2h-1.3zM294.6 25.4h3.1M298.7 24.4v2M299.7 26.4v2.8M300.7 24.4v2M301.8 25.4h3M66 40.6h3.8M66 43.2h3.8M69.8 40.5h1.3v.3h-1.3zM69.8 43.1h1.3v.2h-1.3z"/>
<path d="M204.5 71.1h7.6M205.2 71.9l-1.5 1.5h.8h-.8v-.8M206.5 71.9l-1.5 1.5h.7h-.7v-.8M207 71.1l2.5-1.2v2.5zM207 69.9v2.5"/>
</g>
<circle cx="116.8" cy="254" r="1.27" fill="none" stroke="#840000" stroke-width="1.3"/>
<g fill="#840000" stroke="#840000" stroke-width=".26">
<path d="M298 24.7l.7-.3v2a1.02 1.02 0 0 1-.9-.6 1.02 1.02 0 0 1 .2-1.1z"/>
<path d="M299.2 24.4h1v2h-1z"/>
<path d="M300.7 24.4a1.02 1.02 0 0 1 1 1 1.02 1.02 0 0 1-1 1z"/>
</g>
<path d="M207 24.1h2.5v5.1h-2.5z" fill="#ffffc2"/>
<path d="M203.2 25.4h3.8M203.2 27.9h3.8M207 24.1h2.5v5.1h-2.5zM207 25.3h1.3v.2h-1.3zM207 27.8h1.3v.3h-1.3z" fill="none" stroke="#840000" stroke-width=".26"/>
<path d="M252.7 62.2h2.6v20.4h-2.6z" fill="#ffffc2"/>
<g fill="none" stroke="#840000" stroke-width=".26">
<path d="M248.9 25.4h3.1M253 24.4v2M254 26.4v2.8M255 24.4v2M256 25.4h3.1M248.9 63.5h3.8M248.9 66h3.8M248.9 68.6h3.8M248.9 71.1h3.8M248.9 73.7h3.8M248.9 76.2h3.8M248.9 78.7h3.8"/>
<path d="M252.7 62.2h2.6v20.4h-2.6zM252.7 63.4h1.3v.2h-1.3zM252.7 65.9h1.3v.3h-1.3zM252.7 68.5h1.3v.2h-1.3zM252.7 71h1.3v.2h-1.3zM252.7 73.5h1.3v.3h-1.3zM252.7 76.1h1.3v.2h-1.3zM252.7 78.6h1.3v.3h-1.3zM248.9 81.3h3.8M252.7 81.2h1.3v.2h-1.3z"/>
</g>
<g fill="#840000" stroke="#840000" stroke-width=".26">
<path d="M252.3 24.7l.7-.3v2a1.02 1.02 0 0 1-.9-.6 1.02 1.02 0 0 1 .2-1.1z"/>
<path d="M253.5 24.4h1v2h-1z"/>
<path d="M255 24.4a1.02 1.02 0 0 1 1 1 1.02 1.02 0 0 1-1 1z"/>
</g>
<path d="M298.4 62.2h2.6v20.4h-2.6z" fill="#ffffc2"/>
<g fill="none" stroke="#840000" stroke-width=".26">
<path d="M294.6 63.5h3.8M294.6 66h3.8M294.6 68.6h3.8M294.6 71.1h3.8M294.6 73.7h3.8M294.6 76.2h3.8M294.6 78.7h3.8M298.4 62.2h2.6v20.4h-2.6zM298.4 63.4h1.3v.2h-1.3zM298.4 65.9h1.3v.3h-1.3zM298.4 68.5h1.3v.2h-1.3zM298.4 71h1.3v.2h-1.3z"/>
<path d="M298.4 73.5h1.3v.3h-1.3zM298.4 76.1h1.3v.2h-1.3zM298.4 78.6h1.3v.3h-1.3zM294.6 81.3h3.8M298.4 81.2h1.3v.2h-1.3z"/>
</g>
<path d="M161.3 16.5h2.5v20.3h-2.5z" fill="#ffffc2"/>
<g fill="none" stroke="#840000" stroke-width=".26">
<path d="M157.5 17.8h3.8M161.3 16.5h2.5v20.3h-2.5zM161.3 17.7h1.3v.2h-1.3zM157.5 20.3h3.8M157.5 22.9h3.8M157.5 25.4h3.8M157.5 27.9h3.8M157.5 30.5h3.8M157.5 33h3.8M157.5 35.6h3.8M161.3 20.2h1.3v.2h-1.3zM161.3 22.7h1.3v.3h-1.3z"/>
<path d="M161.3 25.3h1.3v.2h-1.3zM161.3 27.8h1.3v.3h-1.3zM161.3 30.4h1.3v.2h-1.3zM161.3 32.9h1.3v.2h-1.3zM161.3 35.4h1.3v.3h-1.3z"/>
</g>
<g fill="none" stroke="#000084" stroke-width=".26">
<path d="M65.4 7l1.2 1.2M65.4 14.6l1.2 1.2M66.6 7l-1.2 1.2M66.6 14.6l-1.2 1.2M19.7 37.5l1.2 1.2M19.7 35l1.2 1.2M20.9 37.5l-1.2 1.2M20.9 35l-1.2 1.2M111.2 29.9l1.2 1.2M111.2 27.3l1.2 1.2M112.4 29.9l-1.2 1.2M112.4 27.3l-1.2 1.2"/>
<path d="M65.4 42.6l1.2 1.2M66.6 42.6l-1.2 1.2M248.3 75.6l1.2 1.2M248.3 73.1l1.2 1.2M249.5 75.6l-1.2 1.2M249.5 73.1l-1.2 1.2"/>
</g>
<use href="#words"/>
</svg>
